VERSION 5.8 ;
BUSBITCHARS "[]" ;
DIVIDERCHAR "/" ;
UNITS
    DATABASE MICRONS 1000 ;
END UNITS

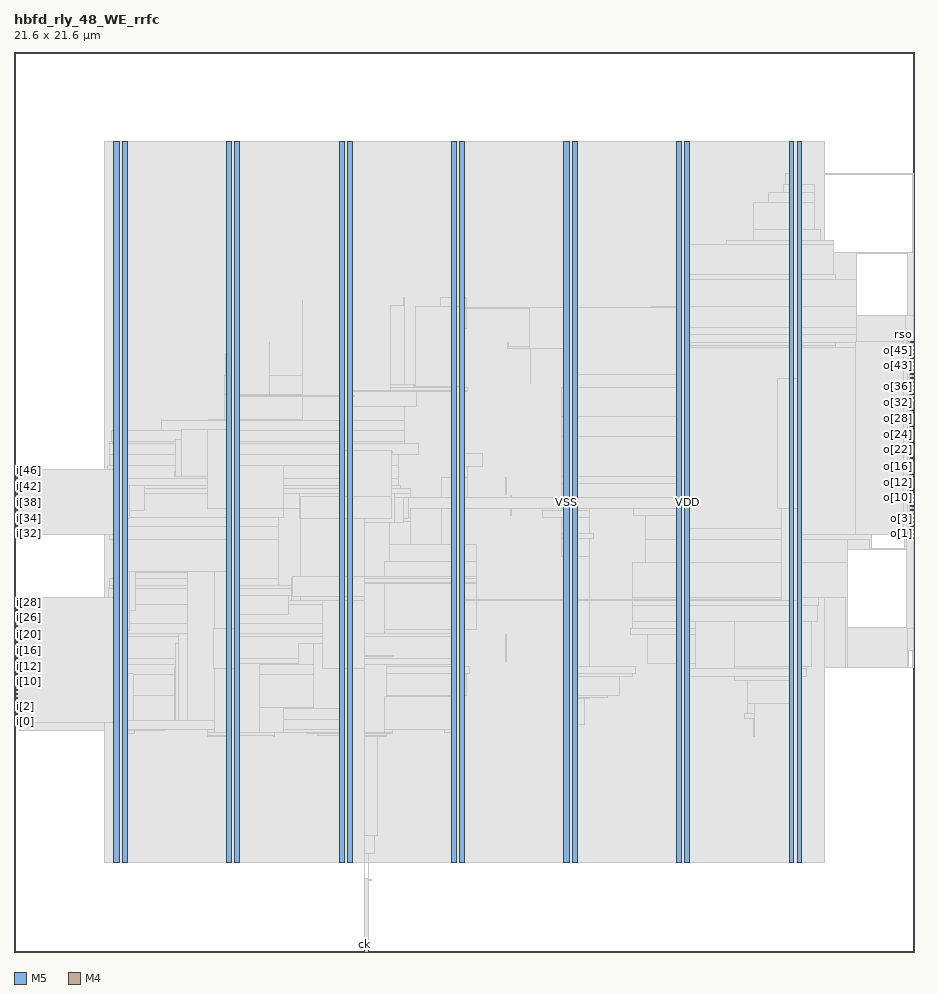
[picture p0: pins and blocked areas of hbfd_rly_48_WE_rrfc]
MACRO hbfd_rly_48_WE_rrfc
  FOREIGN hbfd_rly_48_WE_rrfc 0 0 ;
  CLASS BLOCK ;
  SIZE 21.6 BY 21.6 ;
  PIN ck
    DIRECTION INPUT ;
    USE SIGNAL ;
    PORT
      LAYER M5 ;
        RECT  8.4 0 8.424 0.084 ;
    END
  END ck
  PIN i[0]
    DIRECTION INPUT ;
    USE SIGNAL ;
    PORT
      LAYER M4 ;
        RECT  0 5.52 0.084 5.544 ;
    END
  END i[0]
  PIN i[10]
    DIRECTION INPUT ;
    USE SIGNAL ;
    PORT
      LAYER M4 ;
        RECT  0 6.48 0.084 6.504 ;
    END
  END i[10]
  PIN i[11]
    DIRECTION INPUT ;
    USE SIGNAL ;
    PORT
      LAYER M4 ;
        RECT  0 6.576 0.084 6.6 ;
    END
  END i[11]
  PIN i[12]
    DIRECTION INPUT ;
    USE SIGNAL ;
    PORT
      LAYER M4 ;
        RECT  0 6.672 0.084 6.696 ;
    END
  END i[12]
  PIN i[13]
    DIRECTION INPUT ;
    USE SIGNAL ;
    PORT
      LAYER M4 ;
        RECT  0 6.768 0.084 6.792 ;
    END
  END i[13]
  PIN i[14]
    DIRECTION INPUT ;
    USE SIGNAL ;
    PORT
      LAYER M4 ;
        RECT  0 6.864 0.084 6.888 ;
    END
  END i[14]
  PIN i[15]
    DIRECTION INPUT ;
    USE SIGNAL ;
    PORT
      LAYER M4 ;
        RECT  0 6.96 0.084 6.984 ;
    END
  END i[15]
  PIN i[16]
    DIRECTION INPUT ;
    USE SIGNAL ;
    PORT
      LAYER M4 ;
        RECT  0 7.056 0.084 7.08 ;
    END
  END i[16]
  PIN i[17]
    DIRECTION INPUT ;
    USE SIGNAL ;
    PORT
      LAYER M4 ;
        RECT  0 7.152 0.084 7.176 ;
    END
  END i[17]
  PIN i[18]
    DIRECTION INPUT ;
    USE SIGNAL ;
    PORT
      LAYER M4 ;
        RECT  0 7.248 0.084 7.272 ;
    END
  END i[18]
  PIN i[19]
    DIRECTION INPUT ;
    USE SIGNAL ;
    PORT
      LAYER M4 ;
        RECT  0 7.344 0.084 7.368 ;
    END
  END i[19]
  PIN i[1]
    DIRECTION INPUT ;
    USE SIGNAL ;
    PORT
      LAYER M4 ;
        RECT  0 5.616 0.084 5.64 ;
    END
  END i[1]
  PIN i[20]
    DIRECTION INPUT ;
    USE SIGNAL ;
    PORT
      LAYER M4 ;
        RECT  0 7.44 0.084 7.464 ;
    END
  END i[20]
  PIN i[21]
    DIRECTION INPUT ;
    USE SIGNAL ;
    PORT
      LAYER M4 ;
        RECT  0 7.536 0.084 7.56 ;
    END
  END i[21]
  PIN i[22]
    DIRECTION INPUT ;
    USE SIGNAL ;
    PORT
      LAYER M4 ;
        RECT  0 7.632 0.084 7.656 ;
    END
  END i[22]
  PIN i[23]
    DIRECTION INPUT ;
    USE SIGNAL ;
    PORT
      LAYER M4 ;
        RECT  0 7.728 0.084 7.752 ;
    END
  END i[23]
  PIN i[24]
    DIRECTION INPUT ;
    USE SIGNAL ;
    PORT
      LAYER M4 ;
        RECT  0 7.824 0.084 7.848 ;
    END
  END i[24]
  PIN i[25]
    DIRECTION INPUT ;
    USE SIGNAL ;
    PORT
      LAYER M4 ;
        RECT  0 7.92 0.084 7.944 ;
    END
  END i[25]
  PIN i[26]
    DIRECTION INPUT ;
    USE SIGNAL ;
    PORT
      LAYER M4 ;
        RECT  0 8.016 0.084 8.04 ;
    END
  END i[26]
  PIN i[27]
    DIRECTION INPUT ;
    USE SIGNAL ;
    PORT
      LAYER M4 ;
        RECT  0 8.112 0.084 8.136 ;
    END
  END i[27]
  PIN i[28]
    DIRECTION INPUT ;
    USE SIGNAL ;
    PORT
      LAYER M4 ;
        RECT  0 8.208 0.084 8.232 ;
    END
  END i[28]
  PIN i[29]
    DIRECTION INPUT ;
    USE SIGNAL ;
    PORT
      LAYER M4 ;
        RECT  0 8.304 0.084 8.328 ;
    END
  END i[29]
  PIN i[2]
    DIRECTION INPUT ;
    USE SIGNAL ;
    PORT
      LAYER M4 ;
        RECT  0 5.712 0.084 5.736 ;
    END
  END i[2]
  PIN i[30]
    DIRECTION INPUT ;
    USE SIGNAL ;
    PORT
      LAYER M4 ;
        RECT  0 8.4 0.084 8.424 ;
    END
  END i[30]
  PIN i[31]
    DIRECTION INPUT ;
    USE SIGNAL ;
    PORT
      LAYER M4 ;
        RECT  0 8.496 0.084 8.52 ;
    END
  END i[31]
  PIN i[32]
    DIRECTION INPUT ;
    USE SIGNAL ;
    PORT
      LAYER M4 ;
        RECT  0 10.032 0.084 10.056 ;
    END
  END i[32]
  PIN i[33]
    DIRECTION INPUT ;
    USE SIGNAL ;
    PORT
      LAYER M4 ;
        RECT  0 10.128 0.084 10.152 ;
    END
  END i[33]
  PIN i[34]
    DIRECTION INPUT ;
    USE SIGNAL ;
    PORT
      LAYER M4 ;
        RECT  0 10.224 0.084 10.248 ;
    END
  END i[34]
  PIN i[35]
    DIRECTION INPUT ;
    USE SIGNAL ;
    PORT
      LAYER M4 ;
        RECT  0 10.32 0.084 10.344 ;
    END
  END i[35]
  PIN i[36]
    DIRECTION INPUT ;
    USE SIGNAL ;
    PORT
      LAYER M4 ;
        RECT  0 10.416 0.084 10.44 ;
    END
  END i[36]
  PIN i[37]
    DIRECTION INPUT ;
    USE SIGNAL ;
    PORT
      LAYER M4 ;
        RECT  0 10.512 0.084 10.536 ;
    END
  END i[37]
  PIN i[38]
    DIRECTION INPUT ;
    USE SIGNAL ;
    PORT
      LAYER M4 ;
        RECT  0 10.608 0.084 10.632 ;
    END
  END i[38]
  PIN i[39]
    DIRECTION INPUT ;
    USE SIGNAL ;
    PORT
      LAYER M4 ;
        RECT  0 10.704 0.084 10.728 ;
    END
  END i[39]
  PIN i[3]
    DIRECTION INPUT ;
    USE SIGNAL ;
    PORT
      LAYER M4 ;
        RECT  0 5.808 0.084 5.832 ;
    END
  END i[3]
  PIN i[40]
    DIRECTION INPUT ;
    USE SIGNAL ;
    PORT
      LAYER M4 ;
        RECT  0 10.8 0.084 10.824 ;
    END
  END i[40]
  PIN i[41]
    DIRECTION INPUT ;
    USE SIGNAL ;
    PORT
      LAYER M4 ;
        RECT  0 10.896 0.084 10.92 ;
    END
  END i[41]
  PIN i[42]
    DIRECTION INPUT ;
    USE SIGNAL ;
    PORT
      LAYER M4 ;
        RECT  0 10.992 0.084 11.016 ;
    END
  END i[42]
  PIN i[43]
    DIRECTION INPUT ;
    USE SIGNAL ;
    PORT
      LAYER M4 ;
        RECT  0 11.088 0.084 11.112 ;
    END
  END i[43]
  PIN i[44]
    DIRECTION INPUT ;
    USE SIGNAL ;
    PORT
      LAYER M4 ;
        RECT  0 11.184 0.084 11.208 ;
    END
  END i[44]
  PIN i[45]
    DIRECTION INPUT ;
    USE SIGNAL ;
    PORT
      LAYER M4 ;
        RECT  0 11.28 0.084 11.304 ;
    END
  END i[45]
  PIN i[46]
    DIRECTION INPUT ;
    USE SIGNAL ;
    PORT
      LAYER M4 ;
        RECT  0 11.376 0.084 11.4 ;
    END
  END i[46]
  PIN i[47]
    DIRECTION INPUT ;
    USE SIGNAL ;
    PORT
      LAYER M4 ;
        RECT  0 11.472 0.084 11.496 ;
    END
  END i[47]
  PIN i[4]
    DIRECTION INPUT ;
    USE SIGNAL ;
    PORT
      LAYER M4 ;
        RECT  0 5.904 0.084 5.928 ;
    END
  END i[4]
  PIN i[5]
    DIRECTION INPUT ;
    USE SIGNAL ;
    PORT
      LAYER M4 ;
        RECT  0 6 0.084 6.024 ;
    END
  END i[5]
  PIN i[6]
    DIRECTION INPUT ;
    USE SIGNAL ;
    PORT
      LAYER M4 ;
        RECT  0 6.096 0.084 6.12 ;
    END
  END i[6]
  PIN i[7]
    DIRECTION INPUT ;
    USE SIGNAL ;
    PORT
      LAYER M4 ;
        RECT  0 6.192 0.084 6.216 ;
    END
  END i[7]
  PIN i[8]
    DIRECTION INPUT ;
    USE SIGNAL ;
    PORT
      LAYER M4 ;
        RECT  0 6.288 0.084 6.312 ;
    END
  END i[8]
  PIN i[9]
    DIRECTION INPUT ;
    USE SIGNAL ;
    PORT
      LAYER M4 ;
        RECT  0 6.384 0.084 6.408 ;
    END
  END i[9]
  PIN o[0]
    DIRECTION OUTPUT ;
    USE SIGNAL ;
    PORT
      LAYER M4 ;
        RECT  21.516 9.936 21.6 9.96 ;
    END
  END o[0]
  PIN o[10]
    DIRECTION OUTPUT ;
    USE SIGNAL ;
    PORT
      LAYER M4 ;
        RECT  21.516 10.896 21.6 10.92 ;
    END
  END o[10]
  PIN o[11]
    DIRECTION OUTPUT ;
    USE SIGNAL ;
    PORT
      LAYER M4 ;
        RECT  21.516 10.992 21.6 11.016 ;
    END
  END o[11]
  PIN o[12]
    DIRECTION OUTPUT ;
    USE SIGNAL ;
    PORT
      LAYER M4 ;
        RECT  21.516 11.088 21.6 11.112 ;
    END
  END o[12]
  PIN o[13]
    DIRECTION OUTPUT ;
    USE SIGNAL ;
    PORT
      LAYER M4 ;
        RECT  21.516 11.184 21.6 11.208 ;
    END
  END o[13]
  PIN o[14]
    DIRECTION OUTPUT ;
    USE SIGNAL ;
    PORT
      LAYER M4 ;
        RECT  21.516 11.28 21.6 11.304 ;
    END
  END o[14]
  PIN o[15]
    DIRECTION OUTPUT ;
    USE SIGNAL ;
    PORT
      LAYER M4 ;
        RECT  21.516 11.376 21.6 11.4 ;
    END
  END o[15]
  PIN o[16]
    DIRECTION OUTPUT ;
    USE SIGNAL ;
    PORT
      LAYER M4 ;
        RECT  21.516 11.472 21.6 11.496 ;
    END
  END o[16]
  PIN o[17]
    DIRECTION OUTPUT ;
    USE SIGNAL ;
    PORT
      LAYER M4 ;
        RECT  21.516 11.568 21.6 11.592 ;
    END
  END o[17]
  PIN o[18]
    DIRECTION OUTPUT ;
    USE SIGNAL ;
    PORT
      LAYER M4 ;
        RECT  21.516 11.664 21.6 11.688 ;
    END
  END o[18]
  PIN o[19]
    DIRECTION OUTPUT ;
    USE SIGNAL ;
    PORT
      LAYER M4 ;
        RECT  21.516 11.76 21.6 11.784 ;
    END
  END o[19]
  PIN o[1]
    DIRECTION OUTPUT ;
    USE SIGNAL ;
    PORT
      LAYER M4 ;
        RECT  21.516 10.032 21.6 10.056 ;
    END
  END o[1]
  PIN o[20]
    DIRECTION OUTPUT ;
    USE SIGNAL ;
    PORT
      LAYER M4 ;
        RECT  21.516 11.856 21.6 11.88 ;
    END
  END o[20]
  PIN o[21]
    DIRECTION OUTPUT ;
    USE SIGNAL ;
    PORT
      LAYER M4 ;
        RECT  21.516 11.952 21.6 11.976 ;
    END
  END o[21]
  PIN o[22]
    DIRECTION OUTPUT ;
    USE SIGNAL ;
    PORT
      LAYER M4 ;
        RECT  21.516 12.048 21.6 12.072 ;
    END
  END o[22]
  PIN o[23]
    DIRECTION OUTPUT ;
    USE SIGNAL ;
    PORT
      LAYER M4 ;
        RECT  21.516 12.144 21.6 12.168 ;
    END
  END o[23]
  PIN o[24]
    DIRECTION OUTPUT ;
    USE SIGNAL ;
    PORT
      LAYER M4 ;
        RECT  21.516 12.24 21.6 12.264 ;
    END
  END o[24]
  PIN o[25]
    DIRECTION OUTPUT ;
    USE SIGNAL ;
    PORT
      LAYER M4 ;
        RECT  21.516 12.336 21.6 12.36 ;
    END
  END o[25]
  PIN o[26]
    DIRECTION OUTPUT ;
    USE SIGNAL ;
    PORT
      LAYER M4 ;
        RECT  21.516 12.432 21.6 12.456 ;
    END
  END o[26]
  PIN o[27]
    DIRECTION OUTPUT ;
    USE SIGNAL ;
    PORT
      LAYER M4 ;
        RECT  21.516 12.528 21.6 12.552 ;
    END
  END o[27]
  PIN o[28]
    DIRECTION OUTPUT ;
    USE SIGNAL ;
    PORT
      LAYER M4 ;
        RECT  21.516 12.624 21.6 12.648 ;
    END
  END o[28]
  PIN o[29]
    DIRECTION OUTPUT ;
    USE SIGNAL ;
    PORT
      LAYER M4 ;
        RECT  21.516 12.72 21.6 12.744 ;
    END
  END o[29]
  PIN o[2]
    DIRECTION OUTPUT ;
    USE SIGNAL ;
    PORT
      LAYER M4 ;
        RECT  21.516 10.128 21.6 10.152 ;
    END
  END o[2]
  PIN o[30]
    DIRECTION OUTPUT ;
    USE SIGNAL ;
    PORT
      LAYER M4 ;
        RECT  21.516 12.816 21.6 12.84 ;
    END
  END o[30]
  PIN o[31]
    DIRECTION OUTPUT ;
    USE SIGNAL ;
    PORT
      LAYER M4 ;
        RECT  21.516 12.912 21.6 12.936 ;
    END
  END o[31]
  PIN o[32]
    DIRECTION OUTPUT ;
    USE SIGNAL ;
    PORT
      LAYER M4 ;
        RECT  21.516 13.008 21.6 13.032 ;
    END
  END o[32]
  PIN o[33]
    DIRECTION OUTPUT ;
    USE SIGNAL ;
    PORT
      LAYER M4 ;
        RECT  21.516 13.104 21.6 13.128 ;
    END
  END o[33]
  PIN o[34]
    DIRECTION OUTPUT ;
    USE SIGNAL ;
    PORT
      LAYER M4 ;
        RECT  21.516 13.2 21.6 13.224 ;
    END
  END o[34]
  PIN o[35]
    DIRECTION OUTPUT ;
    USE SIGNAL ;
    PORT
      LAYER M4 ;
        RECT  21.516 13.296 21.6 13.32 ;
    END
  END o[35]
  PIN o[36]
    DIRECTION OUTPUT ;
    USE SIGNAL ;
    PORT
      LAYER M4 ;
        RECT  21.516 13.392 21.6 13.416 ;
    END
  END o[36]
  PIN o[37]
    DIRECTION OUTPUT ;
    USE SIGNAL ;
    PORT
      LAYER M4 ;
        RECT  21.516 13.488 21.6 13.512 ;
    END
  END o[37]
  PIN o[38]
    DIRECTION OUTPUT ;
    USE SIGNAL ;
    PORT
      LAYER M4 ;
        RECT  21.516 13.584 21.6 13.608 ;
    END
  END o[38]
  PIN o[39]
    DIRECTION OUTPUT ;
    USE SIGNAL ;
    PORT
      LAYER M4 ;
        RECT  21.516 13.68 21.6 13.704 ;
    END
  END o[39]
  PIN o[3]
    DIRECTION OUTPUT ;
    USE SIGNAL ;
    PORT
      LAYER M4 ;
        RECT  21.516 10.224 21.6 10.248 ;
    END
  END o[3]
  PIN o[40]
    DIRECTION OUTPUT ;
    USE SIGNAL ;
    PORT
      LAYER M4 ;
        RECT  21.516 13.776 21.6 13.8 ;
    END
  END o[40]
  PIN o[41]
    DIRECTION OUTPUT ;
    USE SIGNAL ;
    PORT
      LAYER M4 ;
        RECT  21.516 13.872 21.6 13.896 ;
    END
  END o[41]
  PIN o[42]
    DIRECTION OUTPUT ;
    USE SIGNAL ;
    PORT
      LAYER M4 ;
        RECT  21.516 13.968 21.6 13.992 ;
    END
  END o[42]
  PIN o[43]
    DIRECTION OUTPUT ;
    USE SIGNAL ;
    PORT
      LAYER M4 ;
        RECT  21.516 14.064 21.6 14.088 ;
    END
  END o[43]
  PIN o[44]
    DIRECTION OUTPUT ;
    USE SIGNAL ;
    PORT
      LAYER M4 ;
        RECT  21.516 14.16 21.6 14.184 ;
    END
  END o[44]
  PIN o[45]
    DIRECTION OUTPUT ;
    USE SIGNAL ;
    PORT
      LAYER M4 ;
        RECT  21.516 14.256 21.6 14.28 ;
    END
  END o[45]
  PIN o[46]
    DIRECTION OUTPUT ;
    USE SIGNAL ;
    PORT
      LAYER M4 ;
        RECT  21.516 14.352 21.6 14.376 ;
    END
  END o[46]
  PIN o[47]
    DIRECTION OUTPUT ;
    USE SIGNAL ;
    PORT
      LAYER M4 ;
        RECT  21.516 14.448 21.6 14.472 ;
    END
  END o[47]
  PIN o[4]
    DIRECTION OUTPUT ;
    USE SIGNAL ;
    PORT
      LAYER M4 ;
        RECT  21.516 10.32 21.6 10.344 ;
    END
  END o[4]
  PIN o[5]
    DIRECTION OUTPUT ;
    USE SIGNAL ;
    PORT
      LAYER M4 ;
        RECT  21.516 10.416 21.6 10.44 ;
    END
  END o[5]
  PIN o[6]
    DIRECTION OUTPUT ;
    USE SIGNAL ;
    PORT
      LAYER M4 ;
        RECT  21.516 10.512 21.6 10.536 ;
    END
  END o[6]
  PIN o[7]
    DIRECTION OUTPUT ;
    USE SIGNAL ;
    PORT
      LAYER M4 ;
        RECT  21.516 10.608 21.6 10.632 ;
    END
  END o[7]
  PIN o[8]
    DIRECTION OUTPUT ;
    USE SIGNAL ;
    PORT
      LAYER M4 ;
        RECT  21.516 10.704 21.6 10.728 ;
    END
  END o[8]
  PIN o[9]
    DIRECTION OUTPUT ;
    USE SIGNAL ;
    PORT
      LAYER M4 ;
        RECT  21.516 10.8 21.6 10.824 ;
    END
  END o[9]
  PIN rfi
    DIRECTION INPUT ;
    USE SIGNAL ;
    PORT
      LAYER M4 ;
        RECT  0 11.568 0.084 11.592 ;
    END
  END rfi
  PIN rfo
    DIRECTION OUTPUT ;
    USE SIGNAL ;
    PORT
      LAYER M4 ;
        RECT  21.516 14.544 21.6 14.568 ;
    END
  END rfo
  PIN rs
    DIRECTION INPUT ;
    USE SIGNAL ;
    PORT
      LAYER M5 ;
        RECT  8.496 0 8.52 0.084 ;
    END
  END rs
  PIN rso
    DIRECTION OUTPUT ;
    USE SIGNAL ;
    PORT
      LAYER M4 ;
        RECT  21.516 14.64 21.6 14.664 ;
    END
  END rso
  PIN VDD
    DIRECTION INOUT ;
    USE POWER ;
    PORT
      LAYER M5 ;
        RECT  18.792 2.151 18.912 19.449 ;
        RECT  16.092 2.151 16.212 19.449 ;
        RECT  13.392 2.151 13.512 19.449 ;
        RECT  10.692 2.151 10.812 19.449 ;
        RECT  7.992 2.151 8.112 19.449 ;
        RECT  5.292 2.151 5.412 19.449 ;
        RECT  2.592 2.151 2.712 19.449 ;
    END
  END VDD
  PIN VSS
    DIRECTION INOUT ;
    USE GROUND ;
    PORT
      LAYER M5 ;
        RECT  18.6 2.137 18.72 19.463 ;
        RECT  15.9 2.137 16.02 19.463 ;
        RECT  13.2 2.137 13.32 19.463 ;
        RECT  10.5 2.137 10.62 19.463 ;
        RECT  7.8 2.137 7.92 19.463 ;
        RECT  5.1 2.137 5.22 19.463 ;
        RECT  2.4 2.137 2.52 19.463 ;
    END
  END VSS
  OBS
    LAYER RVTN ;
     RECT  2.16 2.16 19.44 2.295 ;
     RECT  2.16 2.565 19.44 2.835 ;
     RECT  2.16 3.105 19.44 3.375 ;
     RECT  2.16 3.645 19.44 3.915 ;
     RECT  2.16 4.185 19.44 4.455 ;
     RECT  2.16 4.725 19.44 4.995 ;
     RECT  2.16 5.265 19.44 5.535 ;
     RECT  2.16 5.805 19.44 6.075 ;
     RECT  2.16 6.345 19.44 6.615 ;
     RECT  2.16 6.885 19.44 7.155 ;
     RECT  2.16 7.425 19.44 7.695 ;
     RECT  2.16 7.965 19.44 8.235 ;
     RECT  2.16 8.505 19.44 8.775 ;
     RECT  2.16 9.045 19.44 9.315 ;
     RECT  2.16 9.585 19.44 9.855 ;
     RECT  2.16 10.125 19.44 10.395 ;
     RECT  2.16 10.665 19.44 10.935 ;
     RECT  2.16 11.205 19.44 11.475 ;
     RECT  2.16 11.745 19.44 12.015 ;
     RECT  2.16 12.285 19.44 12.555 ;
     RECT  2.16 12.825 19.44 13.095 ;
     RECT  2.16 13.365 19.44 13.635 ;
     RECT  2.16 13.905 19.44 14.175 ;
     RECT  2.16 14.445 19.44 14.715 ;
     RECT  2.16 14.985 19.44 15.255 ;
     RECT  2.16 15.525 19.44 15.795 ;
     RECT  2.16 16.065 19.44 16.335 ;
     RECT  2.16 16.605 19.44 16.875 ;
     RECT  2.16 17.145 19.44 17.415 ;
     RECT  2.16 17.685 19.44 17.955 ;
     RECT  2.16 18.225 19.44 18.495 ;
     RECT  2.16 18.765 19.44 19.035 ;
     RECT  2.16 19.305 19.44 19.44 ;
    LAYER RVTP ;
     RECT  2.16 2.295 19.44 2.565 ;
     RECT  2.16 2.835 19.44 3.105 ;
     RECT  2.16 3.375 19.44 3.645 ;
     RECT  2.16 3.915 19.44 4.185 ;
     RECT  2.16 4.455 19.44 4.725 ;
     RECT  2.16 4.995 19.44 5.265 ;
     RECT  2.16 5.535 19.44 5.805 ;
     RECT  2.16 6.075 19.44 6.345 ;
     RECT  2.16 6.615 19.44 6.885 ;
     RECT  2.16 7.155 19.44 7.425 ;
     RECT  2.16 7.695 19.44 7.965 ;
     RECT  2.16 8.235 19.44 8.505 ;
     RECT  2.16 8.775 19.44 9.045 ;
     RECT  2.16 9.315 19.44 9.585 ;
     RECT  2.16 9.855 19.44 10.125 ;
     RECT  2.16 10.395 19.44 10.665 ;
     RECT  2.16 10.935 19.44 11.205 ;
     RECT  2.16 11.475 19.44 11.745 ;
     RECT  2.16 12.015 19.44 12.285 ;
     RECT  2.16 12.555 19.44 12.825 ;
     RECT  2.16 13.095 19.44 13.365 ;
     RECT  2.16 13.635 19.44 13.905 ;
     RECT  2.16 14.175 19.44 14.445 ;
     RECT  2.16 14.715 19.44 14.985 ;
     RECT  2.16 15.255 19.44 15.525 ;
     RECT  2.16 15.795 19.44 16.065 ;
     RECT  2.16 16.335 19.44 16.605 ;
     RECT  2.16 16.875 19.44 17.145 ;
     RECT  2.16 17.415 19.44 17.685 ;
     RECT  2.16 17.955 19.44 18.225 ;
     RECT  2.16 18.495 19.44 18.765 ;
     RECT  2.16 19.035 19.44 19.305 ;
    LAYER M1 ;
     RECT  2.16 2.151 19.44 19.449 ;
    LAYER M2 ;
     RECT  0.103 5.508 0.139 5.526 ;
     RECT  0.103 8.28 0.347 8.298 ;
     RECT  0.139 5.31 2.16 5.526 ;
     RECT  0.103 10.17 2.16 10.188 ;
     RECT  2.16 2.151 19.44 19.449 ;
     RECT  19.44 16.11 19.679 17.064 ;
     RECT  19.44 6.822 19.967 13.194 ;
     RECT  19.967 6.822 20.003 8.532 ;
     RECT  19.679 16.11 20.219 16.794 ;
     RECT  19.967 9.666 20.543 12.042 ;
     RECT  20.543 9.666 20.579 9.918 ;
     RECT  20.543 10.908 20.615 11.268 ;
     RECT  20.615 11.25 20.651 11.268 ;
     RECT  20.579 9.666 21.379 9.684 ;
     RECT  19.44 14.49 21.407 15.282 ;
     RECT  20.543 12.024 21.415 12.042 ;
     RECT  19.967 12.834 21.415 13.194 ;
     RECT  20.003 6.822 21.443 7.794 ;
     RECT  21.407 14.49 21.443 15.012 ;
     RECT  21.443 6.822 21.479 7.254 ;
     RECT  21.379 9.666 21.479 10.224 ;
     RECT  20.219 16.776 21.479 16.794 ;
     RECT  21.415 12.024 21.487 13.194 ;
     RECT  21.479 9.666 21.515 9.684 ;
     RECT  21.487 12.024 21.515 13.239 ;
     RECT  21.443 14.994 21.515 15.012 ;
     RECT  21.479 6.822 21.587 6.84 ;
     RECT  21.487 10.98 21.587 10.998 ;
     RECT  21.515 13.221 21.587 13.239 ;
     RECT  19.44 18.666 21.587 18.684 ;
    LAYER M3 ;
     RECT  8.496 1.723 8.514 2.143 ;
     RECT  7.815 2.143 8.514 2.371 ;
     RECT  2.415 2.143 2.505 2.413 ;
     RECT  5.115 2.143 5.205 2.413 ;
     RECT  10.515 2.143 10.605 2.413 ;
     RECT  13.215 2.143 13.305 2.413 ;
     RECT  15.915 2.143 16.005 2.413 ;
     RECT  18.615 2.143 18.705 2.413 ;
     RECT  7.815 2.371 8.658 2.803 ;
     RECT  5.115 2.413 5.397 5.161 ;
     RECT  7.815 2.803 8.73 5.161 ;
     RECT  4.644 5.161 5.397 5.197 ;
     RECT  6.228 5.161 6.246 5.197 ;
     RECT  7.815 5.161 8.946 5.197 ;
     RECT  2.415 2.413 2.697 5.233 ;
     RECT  7.272 5.197 8.946 5.233 ;
     RECT  7.02 5.233 9.09 5.261 ;
     RECT  4.644 5.197 6.246 5.269 ;
     RECT  7.02 5.261 8.154 5.269 ;
     RECT  10.515 2.413 10.797 5.269 ;
     RECT  2.415 5.233 2.898 5.305 ;
     RECT  2.415 5.305 3.618 5.341 ;
     RECT  4.644 5.269 8.154 5.341 ;
     RECT  8.892 5.261 9.09 5.341 ;
     RECT  10.332 5.269 10.797 5.341 ;
     RECT  13.215 2.413 13.497 5.467 ;
     RECT  0.144 5.305 0.162 5.503 ;
     RECT  2.415 5.341 8.154 5.575 ;
     RECT  17.748 5.161 17.766 5.611 ;
     RECT  17.532 5.611 17.766 5.729 ;
     RECT  0.108 5.503 0.162 5.741 ;
     RECT  0.144 5.741 0.162 5.837 ;
     RECT  2.412 5.575 8.154 5.845 ;
     RECT  17.604 5.729 17.766 5.971 ;
     RECT  18.615 2.413 18.897 5.971 ;
     RECT  13.215 5.467 13.698 6.079 ;
     RECT  13.215 6.079 13.806 6.115 ;
     RECT  8.892 5.341 10.797 6.143 ;
     RECT  8.928 6.143 10.797 6.151 ;
     RECT  13.215 6.115 14.238 6.151 ;
     RECT  17.604 5.971 18.897 6.511 ;
     RECT  13.215 6.151 14.526 6.619 ;
     RECT  15.915 2.413 16.197 6.619 ;
     RECT  17.28 6.511 18.897 6.619 ;
     RECT  2.304 5.845 8.154 6.655 ;
     RECT  8.928 6.151 10.854 6.691 ;
     RECT  13.215 6.619 14.85 6.691 ;
     RECT  15.915 6.619 19.026 6.809 ;
     RECT  8.928 6.691 10.926 6.845 ;
     RECT  13.215 6.691 14.922 6.845 ;
     RECT  17.28 6.809 19.026 6.853 ;
     RECT  2.304 6.655 8.19 6.889 ;
     RECT  8.928 6.845 10.797 6.889 ;
     RECT  15.915 6.809 16.362 6.925 ;
     RECT  2.304 6.889 10.797 7.051 ;
     RECT  21.564 6.817 21.582 7.231 ;
     RECT  2.268 7.051 10.797 7.565 ;
     RECT  11.808 6.961 11.826 7.619 ;
     RECT  15.192 6.925 16.362 7.627 ;
     RECT  2.304 7.565 10.797 7.655 ;
     RECT  8.892 7.655 10.797 7.735 ;
     RECT  14.796 7.627 16.362 7.763 ;
     RECT  21.456 7.231 21.582 7.771 ;
     RECT  2.304 7.655 8.154 7.889 ;
     RECT  14.832 7.763 16.362 7.933 ;
     RECT  17.28 6.853 19.134 7.933 ;
     RECT  0.324 8.107 0.342 8.203 ;
     RECT  0.108 8.203 0.342 8.303 ;
     RECT  14.832 7.933 19.278 8.311 ;
     RECT  2.304 7.889 8.097 8.347 ;
     RECT  0.18 8.303 0.342 8.395 ;
     RECT  0.18 8.395 0.378 8.477 ;
     RECT  14.832 8.311 19.314 8.509 ;
     RECT  0.36 8.477 0.378 8.525 ;
     RECT  2.268 8.347 8.097 8.735 ;
     RECT  2.304 8.735 8.097 8.807 ;
     RECT  7.416 8.807 8.097 8.851 ;
     RECT  8.892 7.735 11.106 8.851 ;
     RECT  7.416 8.851 11.106 8.879 ;
     RECT  2.304 8.807 6.354 8.969 ;
     RECT  7.632 8.879 11.106 8.969 ;
     RECT  7.776 8.969 11.106 9.005 ;
     RECT  14.832 8.509 19.998 9.347 ;
     RECT  8.892 9.005 11.106 9.383 ;
     RECT  13.215 6.845 13.806 9.481 ;
     RECT  9 9.383 11.106 9.779 ;
     RECT  2.415 8.969 6.354 9.895 ;
     RECT  15.156 9.347 19.998 9.895 ;
     RECT  13.14 9.481 13.806 9.931 ;
     RECT  13.14 9.931 13.914 10.049 ;
     RECT  7.776 9.005 8.154 10.165 ;
     RECT  21.42 7.771 21.582 10.171 ;
     RECT  2.304 9.895 6.354 10.219 ;
     RECT  21.384 10.171 21.582 10.229 ;
     RECT  7.272 10.165 8.154 10.327 ;
     RECT  9 9.779 9.522 10.327 ;
     RECT  0.108 10.165 0.126 10.349 ;
     RECT  2.268 10.219 6.354 10.427 ;
     RECT  2.304 10.427 6.354 10.435 ;
     RECT  13.14 10.049 13.806 10.435 ;
     RECT  15.156 9.895 20.574 10.471 ;
     RECT  12.672 10.435 13.806 10.589 ;
     RECT  7.272 10.327 9.522 10.741 ;
     RECT  10.26 9.779 10.797 10.741 ;
     RECT  7.272 10.741 10.797 10.859 ;
     RECT  10.26 10.859 10.797 10.867 ;
     RECT  13.14 10.589 13.806 10.903 ;
     RECT  14.868 10.471 20.574 10.903 ;
     RECT  11.916 10.471 11.934 10.967 ;
     RECT  21.42 10.229 21.582 11.003 ;
     RECT  2.304 10.435 6.462 11.011 ;
     RECT  7.272 10.859 9.522 11.011 ;
     RECT  21.42 11.003 21.51 11.021 ;
     RECT  2.304 11.011 9.522 11.129 ;
     RECT  2.304 11.129 9.27 11.201 ;
     RECT  21.42 11.021 21.438 11.213 ;
     RECT  13.14 10.903 20.61 11.245 ;
     RECT  21.348 11.227 21.366 11.245 ;
     RECT  2.304 11.201 9.234 11.371 ;
     RECT  10.26 10.867 10.89 11.399 ;
     RECT  11.808 10.975 11.826 11.399 ;
     RECT  13.14 11.245 21.366 11.405 ;
     RECT  10.515 11.399 10.89 11.641 ;
     RECT  2.232 11.371 9.234 11.669 ;
     RECT  2.304 11.669 9.234 11.947 ;
     RECT  10.515 11.641 11.25 11.975 ;
     RECT  2.304 11.947 9.702 12.209 ;
     RECT  2.304 12.209 9.378 12.245 ;
     RECT  13.14 11.405 20.646 12.365 ;
     RECT  21.492 11.947 21.51 12.451 ;
     RECT  2.34 12.245 9.378 12.515 ;
     RECT  3.528 12.515 9.378 12.749 ;
     RECT  3.528 12.749 3.546 12.785 ;
     RECT  4.68 12.749 6.93 12.785 ;
     RECT  13.14 12.365 19.962 12.845 ;
     RECT  21.42 12.451 21.51 12.859 ;
     RECT  21.348 12.859 21.51 13.037 ;
     RECT  21.42 13.037 21.51 13.085 ;
     RECT  7.815 12.749 9.378 13.099 ;
     RECT  21.456 13.085 21.51 13.216 ;
     RECT  5.04 12.785 6.93 13.373 ;
     RECT  7.815 13.099 9.666 13.441 ;
     RECT  10.515 11.975 10.797 13.441 ;
     RECT  7.815 13.441 10.89 13.469 ;
     RECT  9.036 13.469 10.89 13.559 ;
     RECT  13.14 12.845 19.674 13.559 ;
     RECT  9.036 13.559 9.666 13.613 ;
     RECT  5.04 13.373 5.397 13.829 ;
     RECT  6.12 13.373 6.93 13.829 ;
     RECT  21.456 13.216 21.582 13.963 ;
     RECT  21.42 13.963 21.582 14.059 ;
     RECT  13.215 13.559 19.674 14.251 ;
     RECT  21.384 14.059 21.582 14.347 ;
     RECT  5.076 13.829 5.397 14.369 ;
     RECT  21.24 14.347 21.582 14.477 ;
     RECT  12.384 13.639 12.402 14.485 ;
     RECT  11.844 14.485 12.402 14.525 ;
     RECT  13.215 14.251 19.71 14.549 ;
     RECT  21.312 14.477 21.582 14.549 ;
     RECT  14.22 14.549 19.71 14.635 ;
     RECT  6.12 13.829 6.138 14.639 ;
     RECT  11.844 14.525 11.862 14.639 ;
     RECT  14.22 14.635 20.214 14.819 ;
     RECT  14.22 14.819 14.238 14.909 ;
     RECT  10.515 13.559 10.797 14.953 ;
     RECT  15.12 14.819 20.214 14.981 ;
     RECT  21.384 14.549 21.582 15.287 ;
     RECT  15.3 14.981 20.214 15.485 ;
     RECT  9.036 13.613 9.378 15.521 ;
     RECT  6.912 13.829 6.93 15.629 ;
     RECT  9.36 15.521 9.378 15.719 ;
     RECT  10.224 14.953 10.854 15.719 ;
     RECT  15.915 15.485 20.214 16.133 ;
     RECT  15.915 16.133 19.71 16.259 ;
     RECT  21.456 15.287 21.582 16.799 ;
     RECT  15.915 16.259 19.674 16.979 ;
     RECT  17.1 16.979 19.674 17.069 ;
     RECT  17.748 17.069 19.35 17.339 ;
     RECT  17.748 17.339 19.206 17.987 ;
     RECT  18.108 17.987 19.206 18.221 ;
     RECT  18.468 18.221 19.206 18.419 ;
     RECT  18.504 18.419 18.897 18.689 ;
     RECT  21.564 16.799 21.582 18.689 ;
     RECT  2.415 12.515 2.697 19.187 ;
     RECT  5.115 14.369 5.397 19.187 ;
     RECT  7.815 13.469 8.097 19.187 ;
     RECT  10.515 15.719 10.797 19.187 ;
     RECT  13.215 14.549 13.497 19.187 ;
     RECT  15.915 16.979 16.197 19.187 ;
     RECT  18.615 18.689 18.897 19.187 ;
     RECT  2.415 19.187 2.505 19.457 ;
     RECT  5.115 19.187 5.205 19.457 ;
     RECT  7.815 19.187 7.905 19.457 ;
     RECT  10.515 19.187 10.605 19.457 ;
     RECT  13.215 19.187 13.305 19.457 ;
     RECT  15.915 19.187 16.005 19.457 ;
     RECT  18.615 19.187 18.705 19.457 ;
    LAYER M4 ;
     RECT  0.06 5.52 2.408 8.52 ;
     RECT  0.06 10.032 2.408 11.592 ;
     RECT  2.408 2.148 2.512 19.452 ;
     RECT  2.512 2.418 2.704 19.182 ;
     RECT  2.704 7.728 2.765 9.144 ;
     RECT  2.704 10.416 2.765 11.208 ;
     RECT  2.704 5.568 2.873 6.696 ;
     RECT  2.765 8.208 2.909 9.144 ;
     RECT  2.765 10.608 3.125 11.208 ;
     RECT  2.873 5.568 3.841 6.168 ;
     RECT  3.841 5.568 3.877 6.84 ;
     RECT  3.841 11.424 3.877 11.544 ;
     RECT  3.877 5.568 3.949 7.416 ;
     RECT  3.877 11.424 4.021 12.312 ;
     RECT  3.949 5.568 4.165 7.656 ;
     RECT  2.909 9.12 4.165 9.144 ;
     RECT  4.021 11.424 4.633 12.552 ;
     RECT  4.165 5.568 4.813 9.144 ;
     RECT  4.813 5.28 5.108 9.144 ;
     RECT  4.633 10.656 5.108 12.552 ;
     RECT  5.108 2.148 5.212 19.452 ;
     RECT  5.212 2.418 5.404 19.182 ;
     RECT  5.404 5.28 5.897 6.936 ;
     RECT  5.897 5.28 6.473 5.88 ;
     RECT  5.404 10.656 6.473 11.688 ;
     RECT  5.404 8.112 6.581 8.568 ;
     RECT  6.581 8.448 6.661 8.568 ;
     RECT  5.897 6.912 6.829 6.936 ;
     RECT  6.473 10.656 6.853 11.016 ;
     RECT  6.473 5.856 7.189 5.88 ;
     RECT  6.829 6.912 7.189 7.416 ;
     RECT  7.189 5.856 7.808 7.416 ;
     RECT  6.661 8.448 7.808 9 ;
     RECT  6.853 10.416 7.808 11.016 ;
     RECT  5.404 13.344 7.808 13.368 ;
     RECT  7.808 2.148 7.912 19.452 ;
     RECT  7.912 2.148 8.104 19.182 ;
     RECT  8.104 6.048 8.165 6.072 ;
     RECT  8.104 13.344 8.165 13.368 ;
     RECT  8.104 8.976 8.417 9 ;
     RECT  8.485 1.728 8.569 1.752 ;
     RECT  8.104 12 9.073 12.024 ;
     RECT  8.104 7.104 9.101 7.128 ;
     RECT  8.104 10.32 9.137 11.016 ;
     RECT  9.137 10.32 9.353 10.92 ;
     RECT  9.353 10.416 9.461 10.92 ;
     RECT  9.461 10.656 10.508 10.92 ;
     RECT  9.596 13.584 10.508 13.608 ;
     RECT  9.637 15.456 10.508 15.48 ;
     RECT  10.508 2.148 10.612 19.452 ;
     RECT  10.612 2.418 10.804 19.182 ;
     RECT  10.804 15.456 12.373 15.48 ;
     RECT  10.804 8.448 13.208 8.472 ;
     RECT  10.804 10.656 13.208 10.92 ;
     RECT  12.373 14.496 13.208 15.48 ;
     RECT  13.208 2.148 13.312 19.452 ;
     RECT  13.312 2.418 13.504 19.182 ;
     RECT  13.504 8.448 15.908 8.472 ;
     RECT  13.504 10.656 15.908 10.92 ;
     RECT  13.504 13.872 15.908 15.48 ;
     RECT  15.908 2.148 16.012 19.452 ;
     RECT  16.012 2.418 16.204 19.182 ;
     RECT  16.204 8.448 18.608 8.472 ;
     RECT  16.204 10.176 18.608 14.52 ;
     RECT  18.608 2.148 18.712 19.452 ;
     RECT  18.712 2.418 18.904 19.182 ;
     RECT  18.904 10.032 20.185 14.52 ;
     RECT  20.185 10.032 21.356 14.664 ;
     RECT  21.356 10.032 21.443 14.712 ;
     RECT  21.443 10.032 21.481 14.664 ;
     RECT  21.481 9.936 21.564 14.664 ;
    LAYER M5 ;
     RECT  8.4 0.016 8.52 1.763 ;
     RECT  8.4 1.763 8.424 2.137 ;
     RECT  2.4 2.137 2.52 2.151 ;
     RECT  5.1 2.137 5.22 2.151 ;
     RECT  10.5 2.137 10.62 2.151 ;
     RECT  13.2 2.137 13.32 2.151 ;
     RECT  15.9 2.137 16.02 2.151 ;
     RECT  18.6 2.137 18.72 2.151 ;
     RECT  5.1 2.151 5.412 6.805 ;
     RECT  7.8 2.137 8.424 6.805 ;
     RECT  4.8 6.805 5.412 7.763 ;
     RECT  7.392 6.805 8.424 8.437 ;
     RECT  18.6 2.151 18.912 8.437 ;
     RECT  0.24 8.341 0.264 8.531 ;
     RECT  6.864 8.437 8.424 8.533 ;
     RECT  6.672 8.533 8.424 9.011 ;
     RECT  6.864 9.011 8.424 10.405 ;
     RECT  18.432 8.437 18.912 10.645 ;
     RECT  6.864 10.405 9.048 10.931 ;
     RECT  7.8 10.931 9.048 12.035 ;
     RECT  10.5 2.151 10.812 13.573 ;
     RECT  18.336 10.645 18.912 13.763 ;
     RECT  21.408 14.437 21.432 14.723 ;
     RECT  9.648 13.573 10.812 15.491 ;
     RECT  2.4 2.151 2.712 19.449 ;
     RECT  5.1 7.763 5.412 19.449 ;
     RECT  7.8 12.035 8.112 19.449 ;
     RECT  10.5 15.491 10.812 19.449 ;
     RECT  13.2 2.151 13.512 19.449 ;
     RECT  15.9 2.151 16.212 19.449 ;
     RECT  18.6 13.763 18.912 19.449 ;
     RECT  2.4 19.449 2.52 19.463 ;
     RECT  5.1 19.449 5.22 19.463 ;
     RECT  7.8 19.449 7.92 19.463 ;
     RECT  10.5 19.449 10.62 19.463 ;
     RECT  13.2 19.449 13.32 19.463 ;
     RECT  15.9 19.449 16.02 19.463 ;
     RECT  18.6 19.449 18.72 19.463 ;
  END
END hbfd_rly_48_WE_rrfc
END LIBRARY
